VERSION 5.7 ;
BUSBITCHARS "[]" ;
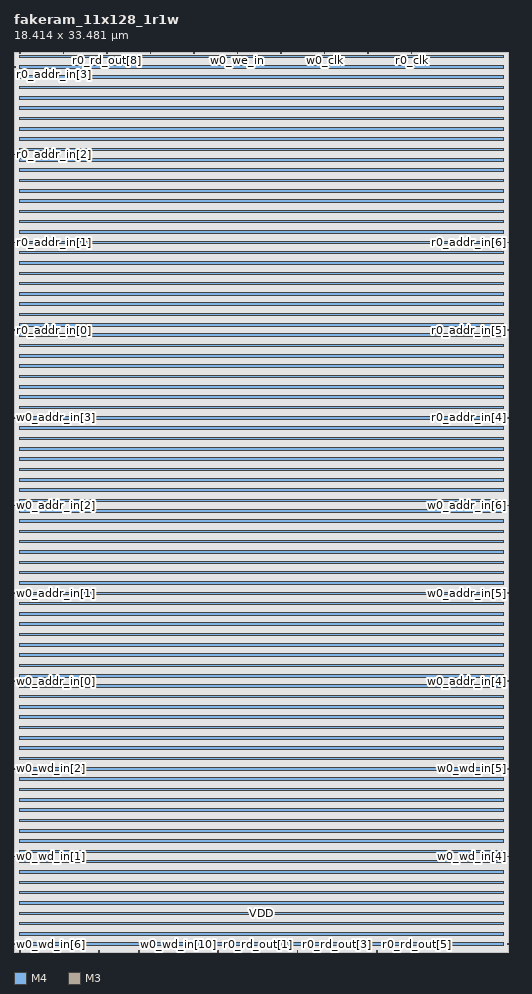
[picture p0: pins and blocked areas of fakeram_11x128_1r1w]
MACRO fakeram_11x128_1r1w
  FOREIGN fakeram_11x128_1r1w 0 0 ;
  SYMMETRY X Y R90 ;
  SIZE 18.414 BY 33.481 ;
  CLASS BLOCK ;
  PIN w0_wd_in[0]
    DIRECTION INPUT ;
    USE SIGNAL ;
    SHAPE ABUTMENT ;
    PORT
      LAYER M4 ;
      RECT 0.000 0.276 0.072 0.300 ;
    END
  END w0_wd_in[0]
  PIN w0_wd_in[1]
    DIRECTION INPUT ;
    USE SIGNAL ;
    SHAPE ABUTMENT ;
    PORT
      LAYER M4 ;
      RECT 0.000 3.540 0.072 3.564 ;
    END
  END w0_wd_in[1]
  PIN w0_wd_in[2]
    DIRECTION INPUT ;
    USE SIGNAL ;
    SHAPE ABUTMENT ;
    PORT
      LAYER M4 ;
      RECT 0.000 6.804 0.072 6.828 ;
    END
  END w0_wd_in[2]
  PIN w0_wd_in[3]
    DIRECTION INPUT ;
    USE SIGNAL ;
    SHAPE ABUTMENT ;
    PORT
      LAYER M4 ;
      RECT 18.342 0.276 18.414 0.300 ;
    END
  END w0_wd_in[3]
  PIN w0_wd_in[4]
    DIRECTION INPUT ;
    USE SIGNAL ;
    SHAPE ABUTMENT ;
    PORT
      LAYER M4 ;
      RECT 18.342 3.540 18.414 3.564 ;
    END
  END w0_wd_in[4]
  PIN w0_wd_in[5]
    DIRECTION INPUT ;
    USE SIGNAL ;
    SHAPE ABUTMENT ;
    PORT
      LAYER M4 ;
      RECT 18.342 6.804 18.414 6.828 ;
    END
  END w0_wd_in[5]
  PIN w0_wd_in[6]
    DIRECTION INPUT ;
    USE SIGNAL ;
    SHAPE ABUTMENT ;
    PORT
      LAYER M3 ;
      RECT 0.207 0.000 0.225 0.054 ;
    END
  END w0_wd_in[6]
  PIN w0_wd_in[7]
    DIRECTION INPUT ;
    USE SIGNAL ;
    SHAPE ABUTMENT ;
    PORT
      LAYER M3 ;
      RECT 1.683 0.000 1.701 0.054 ;
    END
  END w0_wd_in[7]
  PIN w0_wd_in[8]
    DIRECTION INPUT ;
    USE SIGNAL ;
    SHAPE ABUTMENT ;
    PORT
      LAYER M3 ;
      RECT 3.159 0.000 3.177 0.054 ;
    END
  END w0_wd_in[8]
  PIN w0_wd_in[9]
    DIRECTION INPUT ;
    USE SIGNAL ;
    SHAPE ABUTMENT ;
    PORT
      LAYER M3 ;
      RECT 4.635 0.000 4.653 0.054 ;
    END
  END w0_wd_in[9]
  PIN w0_wd_in[10]
    DIRECTION INPUT ;
    USE SIGNAL ;
    SHAPE ABUTMENT ;
    PORT
      LAYER M3 ;
      RECT 6.111 0.000 6.129 0.054 ;
    END
  END w0_wd_in[10]
  PIN r0_rd_out[0]
    DIRECTION OUTPUT ;
    USE SIGNAL ;
    SHAPE ABUTMENT ;
    PORT
      LAYER M3 ;
      RECT 7.587 0.000 7.605 0.054 ;
    END
  END r0_rd_out[0]
  PIN r0_rd_out[1]
    DIRECTION OUTPUT ;
    USE SIGNAL ;
    SHAPE ABUTMENT ;
    PORT
      LAYER M3 ;
      RECT 9.063 0.000 9.081 0.054 ;
    END
  END r0_rd_out[1]
  PIN r0_rd_out[2]
    DIRECTION OUTPUT ;
    USE SIGNAL ;
    SHAPE ABUTMENT ;
    PORT
      LAYER M3 ;
      RECT 10.539 0.000 10.557 0.054 ;
    END
  END r0_rd_out[2]
  PIN r0_rd_out[3]
    DIRECTION OUTPUT ;
    USE SIGNAL ;
    SHAPE ABUTMENT ;
    PORT
      LAYER M3 ;
      RECT 12.015 0.000 12.033 0.054 ;
    END
  END r0_rd_out[3]
  PIN r0_rd_out[4]
    DIRECTION OUTPUT ;
    USE SIGNAL ;
    SHAPE ABUTMENT ;
    PORT
      LAYER M3 ;
      RECT 13.491 0.000 13.509 0.054 ;
    END
  END r0_rd_out[4]
  PIN r0_rd_out[5]
    DIRECTION OUTPUT ;
    USE SIGNAL ;
    SHAPE ABUTMENT ;
    PORT
      LAYER M3 ;
      RECT 14.967 0.000 14.985 0.054 ;
    END
  END r0_rd_out[5]
  PIN r0_rd_out[6]
    DIRECTION OUTPUT ;
    USE SIGNAL ;
    SHAPE ABUTMENT ;
    PORT
      LAYER M3 ;
      RECT 0.207 33.427 0.225 33.481 ;
    END
  END r0_rd_out[6]
  PIN r0_rd_out[7]
    DIRECTION OUTPUT ;
    USE SIGNAL ;
    SHAPE ABUTMENT ;
    PORT
      LAYER M3 ;
      RECT 1.827 33.427 1.845 33.481 ;
    END
  END r0_rd_out[7]
  PIN r0_rd_out[8]
    DIRECTION OUTPUT ;
    USE SIGNAL ;
    SHAPE ABUTMENT ;
    PORT
      LAYER M3 ;
      RECT 3.447 33.427 3.465 33.481 ;
    END
  END r0_rd_out[8]
  PIN r0_rd_out[9]
    DIRECTION OUTPUT ;
    USE SIGNAL ;
    SHAPE ABUTMENT ;
    PORT
      LAYER M3 ;
      RECT 5.067 33.427 5.085 33.481 ;
    END
  END r0_rd_out[9]
  PIN r0_rd_out[10]
    DIRECTION OUTPUT ;
    USE SIGNAL ;
    SHAPE ABUTMENT ;
    PORT
      LAYER M3 ;
      RECT 6.687 33.427 6.705 33.481 ;
    END
  END r0_rd_out[10]
  PIN w0_addr_in[0]
    DIRECTION INPUT ;
    USE SIGNAL ;
    SHAPE ABUTMENT ;
    PORT
      LAYER M4 ;
      RECT 0.000 10.068 0.072 10.092 ;
    END
  END w0_addr_in[0]
  PIN w0_addr_in[1]
    DIRECTION INPUT ;
    USE SIGNAL ;
    SHAPE ABUTMENT ;
    PORT
      LAYER M4 ;
      RECT 0.000 13.332 0.072 13.356 ;
    END
  END w0_addr_in[1]
  PIN w0_addr_in[2]
    DIRECTION INPUT ;
    USE SIGNAL ;
    SHAPE ABUTMENT ;
    PORT
      LAYER M4 ;
      RECT 0.000 16.596 0.072 16.620 ;
    END
  END w0_addr_in[2]
  PIN w0_addr_in[3]
    DIRECTION INPUT ;
    USE SIGNAL ;
    SHAPE ABUTMENT ;
    PORT
      LAYER M4 ;
      RECT 0.000 19.860 0.072 19.884 ;
    END
  END w0_addr_in[3]
  PIN w0_addr_in[4]
    DIRECTION INPUT ;
    USE SIGNAL ;
    SHAPE ABUTMENT ;
    PORT
      LAYER M4 ;
      RECT 18.342 10.068 18.414 10.092 ;
    END
  END w0_addr_in[4]
  PIN w0_addr_in[5]
    DIRECTION INPUT ;
    USE SIGNAL ;
    SHAPE ABUTMENT ;
    PORT
      LAYER M4 ;
      RECT 18.342 13.332 18.414 13.356 ;
    END
  END w0_addr_in[5]
  PIN w0_addr_in[6]
    DIRECTION INPUT ;
    USE SIGNAL ;
    SHAPE ABUTMENT ;
    PORT
      LAYER M4 ;
      RECT 18.342 16.596 18.414 16.620 ;
    END
  END w0_addr_in[6]
  PIN r0_addr_in[0]
    DIRECTION INPUT ;
    USE SIGNAL ;
    SHAPE ABUTMENT ;
    PORT
      LAYER M4 ;
      RECT 0.000 23.124 0.072 23.148 ;
    END
  END r0_addr_in[0]
  PIN r0_addr_in[1]
    DIRECTION INPUT ;
    USE SIGNAL ;
    SHAPE ABUTMENT ;
    PORT
      LAYER M4 ;
      RECT 0.000 26.388 0.072 26.412 ;
    END
  END r0_addr_in[1]
  PIN r0_addr_in[2]
    DIRECTION INPUT ;
    USE SIGNAL ;
    SHAPE ABUTMENT ;
    PORT
      LAYER M4 ;
      RECT 0.000 29.652 0.072 29.676 ;
    END
  END r0_addr_in[2]
  PIN r0_addr_in[3]
    DIRECTION INPUT ;
    USE SIGNAL ;
    SHAPE ABUTMENT ;
    PORT
      LAYER M4 ;
      RECT 0.000 32.916 0.072 32.940 ;
    END
  END r0_addr_in[3]
  PIN r0_addr_in[4]
    DIRECTION INPUT ;
    USE SIGNAL ;
    SHAPE ABUTMENT ;
    PORT
      LAYER M4 ;
      RECT 18.342 19.860 18.414 19.884 ;
    END
  END r0_addr_in[4]
  PIN r0_addr_in[5]
    DIRECTION INPUT ;
    USE SIGNAL ;
    SHAPE ABUTMENT ;
    PORT
      LAYER M4 ;
      RECT 18.342 23.124 18.414 23.148 ;
    END
  END r0_addr_in[5]
  PIN r0_addr_in[6]
    DIRECTION INPUT ;
    USE SIGNAL ;
    SHAPE ABUTMENT ;
    PORT
      LAYER M4 ;
      RECT 18.342 26.388 18.414 26.412 ;
    END
  END r0_addr_in[6]
  PIN w0_we_in
    DIRECTION INPUT ;
    USE SIGNAL ;
    SHAPE ABUTMENT ;
    PORT
      LAYER M3 ;
      RECT 8.307 33.427 8.325 33.481 ;
    END
  END w0_we_in
  PIN w0_ce_in
    DIRECTION INPUT ;
    USE SIGNAL ;
    SHAPE ABUTMENT ;
    PORT
      LAYER M3 ;
      RECT 9.927 33.427 9.945 33.481 ;
    END
  END w0_ce_in
  PIN w0_clk
    DIRECTION INPUT ;
    USE SIGNAL ;
    SHAPE ABUTMENT ;
    PORT
      LAYER M3 ;
      RECT 11.547 33.427 11.565 33.481 ;
    END
  END w0_clk
  PIN r0_ce_in
    DIRECTION INPUT ;
    USE SIGNAL ;
    SHAPE ABUTMENT ;
    PORT
      LAYER M3 ;
      RECT 13.167 33.427 13.185 33.481 ;
    END
  END r0_ce_in
  PIN r0_clk
    DIRECTION INPUT ;
    USE SIGNAL ;
    SHAPE ABUTMENT ;
    PORT
      LAYER M3 ;
      RECT 14.787 33.427 14.805 33.481 ;
    END
  END r0_clk
  PIN VSS
    DIRECTION INOUT ;
    USE GROUND ;
    PORT
      LAYER M4 ;
      RECT 0.216 0.240 18.198 0.336 ;
      RECT 0.216 1.008 18.198 1.104 ;
      RECT 0.216 1.776 18.198 1.872 ;
      RECT 0.216 2.544 18.198 2.640 ;
      RECT 0.216 3.312 18.198 3.408 ;
      RECT 0.216 4.080 18.198 4.176 ;
      RECT 0.216 4.848 18.198 4.944 ;
      RECT 0.216 5.616 18.198 5.712 ;
      RECT 0.216 6.384 18.198 6.480 ;
      RECT 0.216 7.152 18.198 7.248 ;
      RECT 0.216 7.920 18.198 8.016 ;
      RECT 0.216 8.688 18.198 8.784 ;
      RECT 0.216 9.456 18.198 9.552 ;
      RECT 0.216 10.224 18.198 10.320 ;
      RECT 0.216 10.992 18.198 11.088 ;
      RECT 0.216 11.760 18.198 11.856 ;
      RECT 0.216 12.528 18.198 12.624 ;
      RECT 0.216 13.296 18.198 13.392 ;
      RECT 0.216 14.064 18.198 14.160 ;
      RECT 0.216 14.832 18.198 14.928 ;
      RECT 0.216 15.600 18.198 15.696 ;
      RECT 0.216 16.368 18.198 16.464 ;
      RECT 0.216 17.136 18.198 17.232 ;
      RECT 0.216 17.904 18.198 18.000 ;
      RECT 0.216 18.672 18.198 18.768 ;
      RECT 0.216 19.440 18.198 19.536 ;
      RECT 0.216 20.208 18.198 20.304 ;
      RECT 0.216 20.976 18.198 21.072 ;
      RECT 0.216 21.744 18.198 21.840 ;
      RECT 0.216 22.512 18.198 22.608 ;
      RECT 0.216 23.280 18.198 23.376 ;
      RECT 0.216 24.048 18.198 24.144 ;
      RECT 0.216 24.816 18.198 24.912 ;
      RECT 0.216 25.584 18.198 25.680 ;
      RECT 0.216 26.352 18.198 26.448 ;
      RECT 0.216 27.120 18.198 27.216 ;
      RECT 0.216 27.888 18.198 27.984 ;
      RECT 0.216 28.656 18.198 28.752 ;
      RECT 0.216 29.424 18.198 29.520 ;
      RECT 0.216 30.192 18.198 30.288 ;
      RECT 0.216 30.960 18.198 31.056 ;
      RECT 0.216 31.728 18.198 31.824 ;
      RECT 0.216 32.496 18.198 32.592 ;
      RECT 0.216 33.264 18.198 33.360 ;
    END
  END VSS
  PIN VDD
    DIRECTION INOUT ;
    USE POWER ;
    PORT
      LAYER M4 ;
      RECT 0.216 0.624 18.198 0.720 ;
      RECT 0.216 1.392 18.198 1.488 ;
      RECT 0.216 2.160 18.198 2.256 ;
      RECT 0.216 2.928 18.198 3.024 ;
      RECT 0.216 3.696 18.198 3.792 ;
      RECT 0.216 4.464 18.198 4.560 ;
      RECT 0.216 5.232 18.198 5.328 ;
      RECT 0.216 6.000 18.198 6.096 ;
      RECT 0.216 6.768 18.198 6.864 ;
      RECT 0.216 7.536 18.198 7.632 ;
      RECT 0.216 8.304 18.198 8.400 ;
      RECT 0.216 9.072 18.198 9.168 ;
      RECT 0.216 9.840 18.198 9.936 ;
      RECT 0.216 10.608 18.198 10.704 ;
      RECT 0.216 11.376 18.198 11.472 ;
      RECT 0.216 12.144 18.198 12.240 ;
      RECT 0.216 12.912 18.198 13.008 ;
      RECT 0.216 13.680 18.198 13.776 ;
      RECT 0.216 14.448 18.198 14.544 ;
      RECT 0.216 15.216 18.198 15.312 ;
      RECT 0.216 15.984 18.198 16.080 ;
      RECT 0.216 16.752 18.198 16.848 ;
      RECT 0.216 17.520 18.198 17.616 ;
      RECT 0.216 18.288 18.198 18.384 ;
      RECT 0.216 19.056 18.198 19.152 ;
      RECT 0.216 19.824 18.198 19.920 ;
      RECT 0.216 20.592 18.198 20.688 ;
      RECT 0.216 21.360 18.198 21.456 ;
      RECT 0.216 22.128 18.198 22.224 ;
      RECT 0.216 22.896 18.198 22.992 ;
      RECT 0.216 23.664 18.198 23.760 ;
      RECT 0.216 24.432 18.198 24.528 ;
      RECT 0.216 25.200 18.198 25.296 ;
      RECT 0.216 25.968 18.198 26.064 ;
      RECT 0.216 26.736 18.198 26.832 ;
      RECT 0.216 27.504 18.198 27.600 ;
      RECT 0.216 28.272 18.198 28.368 ;
      RECT 0.216 29.040 18.198 29.136 ;
      RECT 0.216 29.808 18.198 29.904 ;
      RECT 0.216 30.576 18.198 30.672 ;
      RECT 0.216 31.344 18.198 31.440 ;
      RECT 0.216 32.112 18.198 32.208 ;
      RECT 0.216 32.880 18.198 32.976 ;
    END
  END VDD
  OBS
    LAYER M1 ;
    RECT 0 0 18.414 33.481 ;
    LAYER M2 ;
    RECT 0 0 18.414 33.481 ;
    LAYER M3 ;
    RECT 0 0 18.414 33.481 ;
    LAYER M4 ;
    RECT 0 0 18.414 33.481 ;
  END
END fakeram_11x128_1r1w

END LIBRARY
